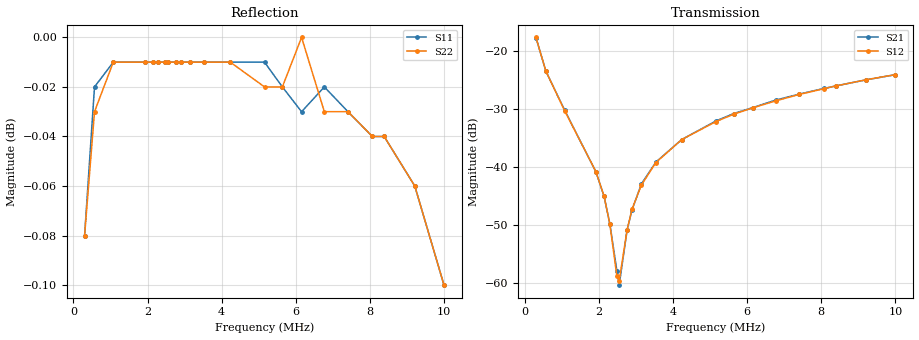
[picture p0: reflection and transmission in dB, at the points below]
!s-Parameter Generated by FASTRON Sdn. Bhd.
!FASTRON P/N : 1812AFTC-401X
!Keysight Technologies: E5071C_MY46733604_B.14.02
!Date: Wed Mar 18 13:58:13 2026
!Version  :Rev00  Wed Mar 18 13:58:13 2026
!Data & Calibration Information:
!Freq  S11:SOLT2(ON)  S21:SOLT2(ON)  S12:SOLT2(ON)  S22:SOLT2(ON)
!PortZ  Port1:50+j0  Port2:50+j0
!When reading reference impedance value at option line is always used.
! Remarks : This data is being provided solely for informational purposes.
# Hz S dB R 50
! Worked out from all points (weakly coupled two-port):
!   1601 points, 300 kHz to 10 MHz, reference 50 ohm
!   highest |S21| = -17.61 dB at 300 kHz (marker M1); lowest = -60.4 dB at 2.546 MHz (marker M2)
!   lowest |S11| = -0.1 dB at 10 MHz (marker M3), VSWR 180.75, Z = 4.71 - j200 ohm
!   |S11| at or under -10 dB: nowhere
!   |S22| runs from -0.1 to 0.0 dB; largest |S21 - S12| = 0.0009
!   S11 on the Smith chart (normalised r, x): 300 kHz: 0.21, +6.60; 2.295 MHz: 0.00, +1.25; 4.233 MHz: 0.00, +0.35; 6.156 MHz: 0.00, -0.22; 8.066 MHz: 0.00, -0.96; 10 MHz: 0.09, -4.00
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300000  -0.08 17.2  -17.61 -81.0  -17.59 -81.1  -0.08 -3.8
567669  -0.02 22.7  -23.41 -85.6  -23.42 -85.8  -0.03 -17.2
1074159  -0.01 37.7  -30.14 -88.2  -30.25 -88.4  -0.01 -37.7
1917564  -0.01 64.8  -40.79 -86.0  -40.77 -87.2  -0.01 -69.9
2137427  -0.01 72.0  -45.02 -83.3  -44.96 -82.6  -0.01 -78.1
2294736  -0.01 77.1  -49.78 -78.9  -49.86 -79.0  -0.01 -84.0
2483508  -0.01 83.3  -57.85 -30.9  -58.76 -33.2  -0.01 -91.1
2546432  -0.01 85.4  -60.37 -11.4  -59.61 9.0  -0.01 -93.4
2761422  -0.01 92.5  -50.83 66.9  -50.80 68.1  -0.01 -101.5
2892776  -0.01 96.8  -47.40 72.7  -47.25 71.0  -0.01 -106.4
3145219  -0.01 105.1  -42.90 74.3  -43.10 75.3  -0.01 -115.8
3534704  -0.01 117.9  -39.14 77.8  -39.22 77.5  -0.01 -130.3
4233021  -0.01 141.0  -35.23 77.8  -35.24 77.8  -0.01 -156.3
5155786  -0.01 171.6  -32.03 77.1  -32.14 77.0  -0.02 169.5
5637569  -0.02 -172.5  -30.74 76.1  -30.85 76.4  -0.02 151.6
6156194  -0.03 -155.3  -29.70 75.2  -29.75 75.8  -0.00 132.4
6770355  -0.02 -135.0  -28.42 73.9  -28.55 74.1  -0.03 109.5
7409041  -0.03 -113.8  -27.38 72.6  -27.44 72.6  -0.03 85.9
8066168  -0.04 -92.1  -26.41 70.7  -26.46 70.7  -0.04 61.5
8385344  -0.04 -81.5  -25.98 69.7  -25.99 69.7  -0.04 49.6
9211447  -0.06 -54.2  -24.92 66.6  -24.90 66.7  -0.06 18.9
1e7  -0.10 -28.0  -24.04 62.3  -24.02 62.3  -0.10 -10.3
